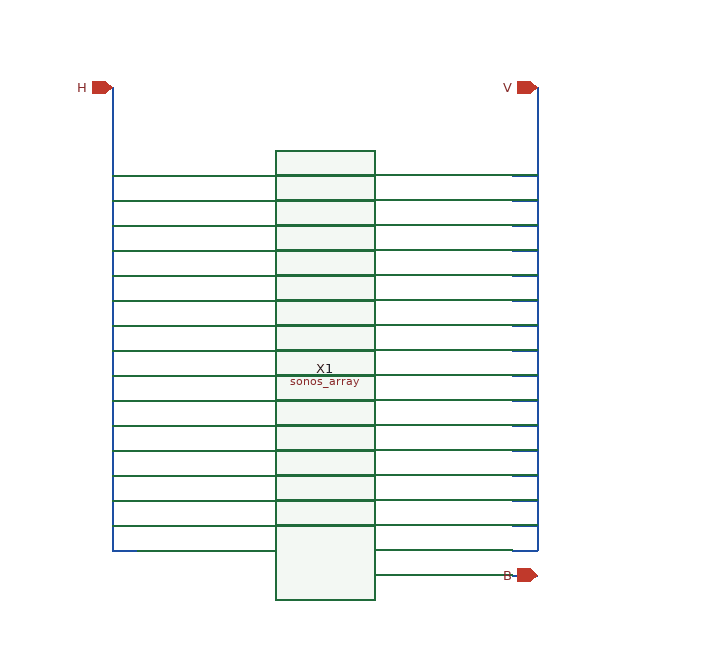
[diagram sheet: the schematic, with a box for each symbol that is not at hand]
v {xschem version=3.1.0 file_version=1.2
}
G {}
K {}
V {}
S {}
E {}
N 80 -120 90 -120 {
lab=H}
N 70 -120 80 -120 {
lab=H}
N 70 -490 70 -120 {
lab=H}
N 70 -420 90 -420 {
lab=H}
N 70 -400 90 -400 {
lab=H}
N 70 -380 90 -380 {
lab=H}
N 70 -360 90 -360 {
lab=H}
N 70 -340 90 -340 {
lab=H}
N 70 -320 90 -320 {
lab=H}
N 70 -300 90 -300 {
lab=H}
N 70 -280 90 -280 {
lab=H}
N 70 -260 90 -260 {
lab=H}
N 70 -240 90 -240 {
lab=H}
N 70 -220 90 -220 {
lab=H}
N 70 -200 90 -200 {
lab=H}
N 70 -180 90 -180 {
lab=H}
N 70 -160 90 -160 {
lab=H}
N 70 -140 90 -140 {
lab=H}
N 410 -490 410 -120 {
lab=V}
N 390 -420 410 -420 {
lab=V}
N 390 -400 410 -400 {
lab=V}
N 390 -380 410 -380 {
lab=V}
N 390 -360 410 -360 {
lab=V}
N 390 -340 410 -340 {
lab=V}
N 390 -320 410 -320 {
lab=V}
N 390 -300 410 -300 {
lab=V}
N 390 -280 410 -280 {
lab=V}
N 390 -260 410 -260 {
lab=V}
N 390 -240 410 -240 {
lab=V}
N 390 -220 410 -220 {
lab=V}
N 390 -200 410 -200 {
lab=V}
N 390 -180 410 -180 {
lab=V}
N 390 -160 410 -160 {
lab=V}
N 390 -140 410 -140 {
lab=V}
N 390 -120 410 -120 {
lab=V}
N 390 -100 410 -100 {
lab=#net1}
C {sonos_array.sym} 240 -260 0 0 {name=X1}
C {devices/ipin.sym} 70 -490 1 0 {name=p1 lab=H
}
C {devices/iopin.sym} 410 -490 3 0 {name=p1 lab=V}
C {devices/iopin.sym} 410 -100 0 0 {name=p1 lab=B}
